VERSION 5.7 ;
  NOWIREEXTENSIONATPIN ON ;
  DIVIDERCHAR "/" ;
  BUSBITCHARS "[]" ;
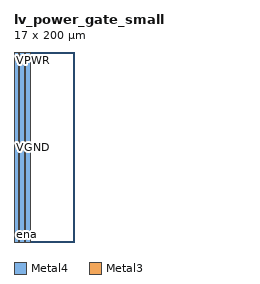
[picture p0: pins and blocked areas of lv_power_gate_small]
MACRO lv_power_gate_small
  CLASS BLOCK ;
  FOREIGN lv_power_gate_small ;
  ORIGIN 0.000 0.000 ;
  SIZE 17.000 BY 200.000 ;
  PIN VGND
    DIRECTION INOUT ;
    USE GROUND ;
    PORT
      LAYER Metal4 ;
        RECT 0.000 0.000 5.000 200.000 ;
    END
  END VGND
  PIN VPWR
    DIRECTION INOUT ;
    USE POWER ;
    PORT
      LAYER Metal4 ;
        RECT 6.000 0.000 11.000 200.000 ;
    END
  END VPWR
  PIN VPWR_SW
    DIRECTION INOUT ;
    USE POWER ;
    PORT
      LAYER Metal4 ;
        RECT 12.000 0.000 17.000 200.000 ;
    END
  END VPWR_SW
  PIN ena
    DIRECTION INPUT ;
    USE SIGNAL ;
    PORT
      LAYER Metal3 ;
        RECT 0.000 0.000 0.400 0.400 ;
    END
  END ena
END lv_power_gate_small
END LIBRARY

